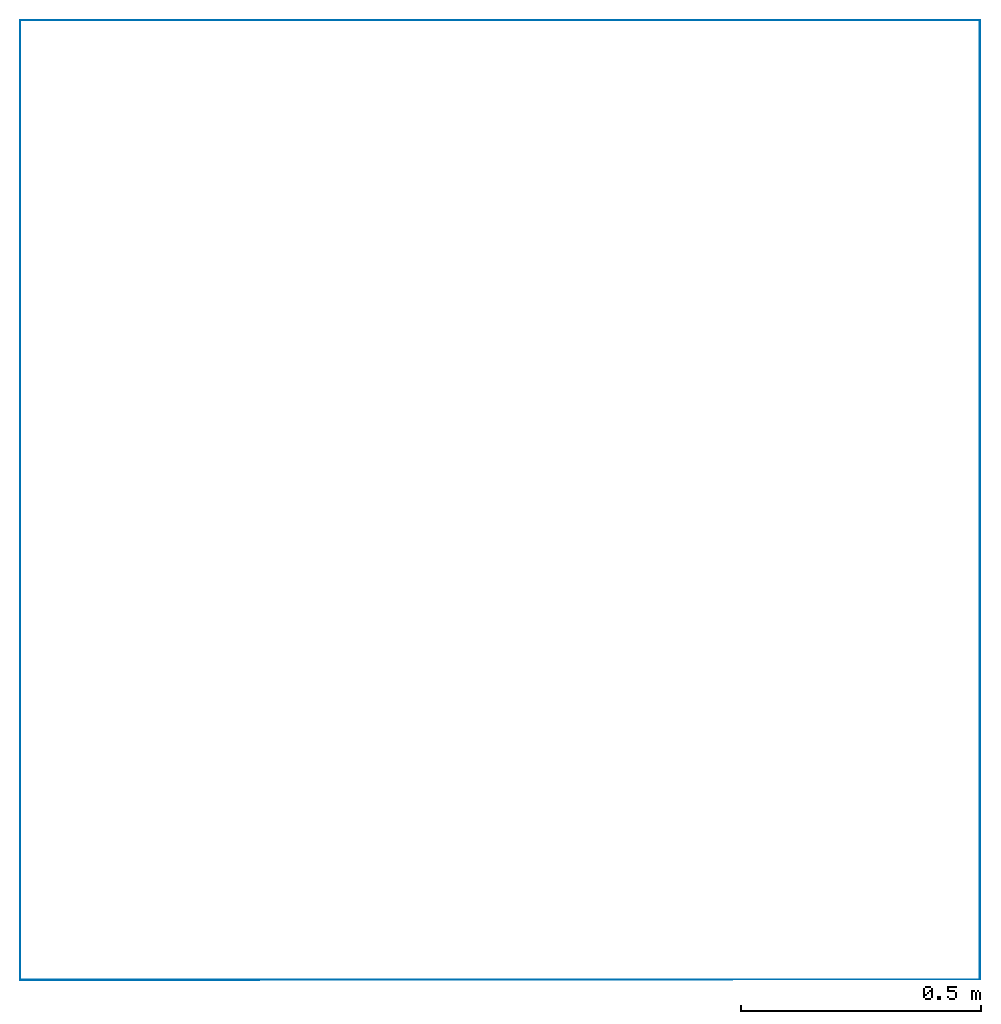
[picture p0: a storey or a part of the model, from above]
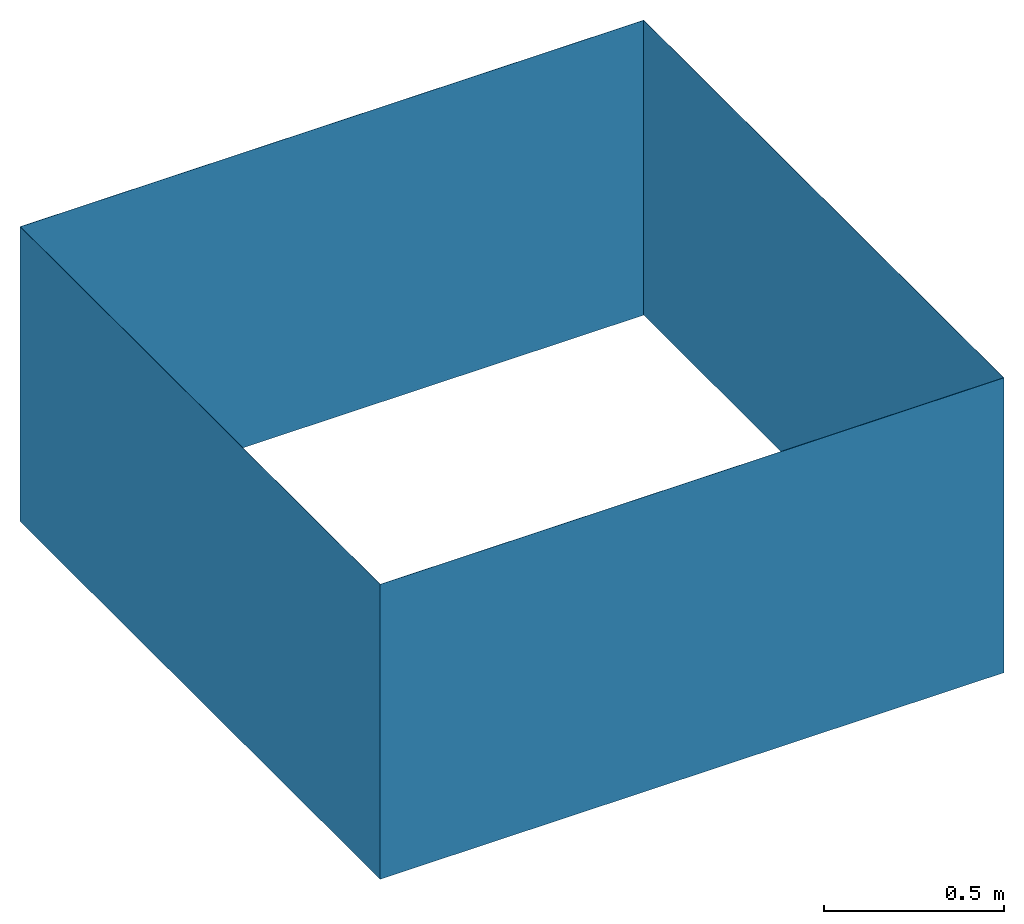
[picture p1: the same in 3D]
Properties of the parts of a building model (IFC4)

# File
Description: ViewDefinition [ReferenceView_V1.2], ExchangeRequirement [Architecture], Option [Elements to export: Entire project], Option [Partial Structure Display: Entire Model], Option [IFC Domain: All], Option [Structural Function: All Elements], Option [Convert Grid elements: On], Option [Convert IFC Annotations and Archicad 2D elements: Off], Option [Convert 2D symbols of Doors and Windows: Off], Option [Export geometries that Participates in Collision Detection only: On], Option [Split complex elements: Off], Option [Material Preservation: Explode all], Option [IFC Model position: Survey Point and Project Origin], Option [Curtain Wall export mode: Single Element], Option [Railing export mode: Single Element], Option [Stair export mode: Single Element], Option [Properties To Export: All properties], Option [Space containment: Off], Option [Geometry to type objects: Off], Option [Element Properties: Off], Option [Building Material Properties: Off], Option [Element Parameters: Off], Option [Component Parameters: Off], Option [IFC Base Quantities: Off], Option [Door Window Parameters: On], Option [IFC Space boundaries: Off], Option [Archicad Zone Categories as IFC Space classification data: Off], Option [Element Classifications: On]
File name: /Users/Wing_1/Zoho WorkDrive (Archpolis Ltd.)/10_Project/22007-ASD5OK136/Solibri_Intersection_volume.ifc
Time: 2023-02-20T17:10:20
Author: Architect
Organization: Building Designer Office
Written by: DDS_IFC v3.0
Made in: IFC file generated by Graphisoft Archicad 26.0.0 INT FULL Macintosh version (IFC add-on version: 4024 INT FULL).
Authorization: The authorising person

# IfcSite, Site
RefLatitude: 47, 33, 34, 948800; RefLongitude: 19, 3, 17, 204400; RefElevation: 0 mm

# IfcBuildingStorey (3)
In: Building
Name | Elevation (mm)
Ground Floor | 0
2. Story | 6000
1. Story | 3000

# IfcSpace: Generic, 07
In: Ground Floor
Type - PredefinedType: SPACE
LongName: COVERAGE; Classification: Space (Archicad Classification)
Pset_SpaceOccupancyRequirements - OccupancyNumber: 14; AreaPerOccupant: 6 m2
Pset_SpaceCommon - Reference: Space

# IfcWall: GENERIC - STRUCTURAL 1 (4)
In: Ground Floor
Type - PredefinedType: PARAPET
Classification: Parapet Wall (Archicad Classification); Material: GENERIC - STRUCTURAL
Pset_WallCommon - Status: NEW
